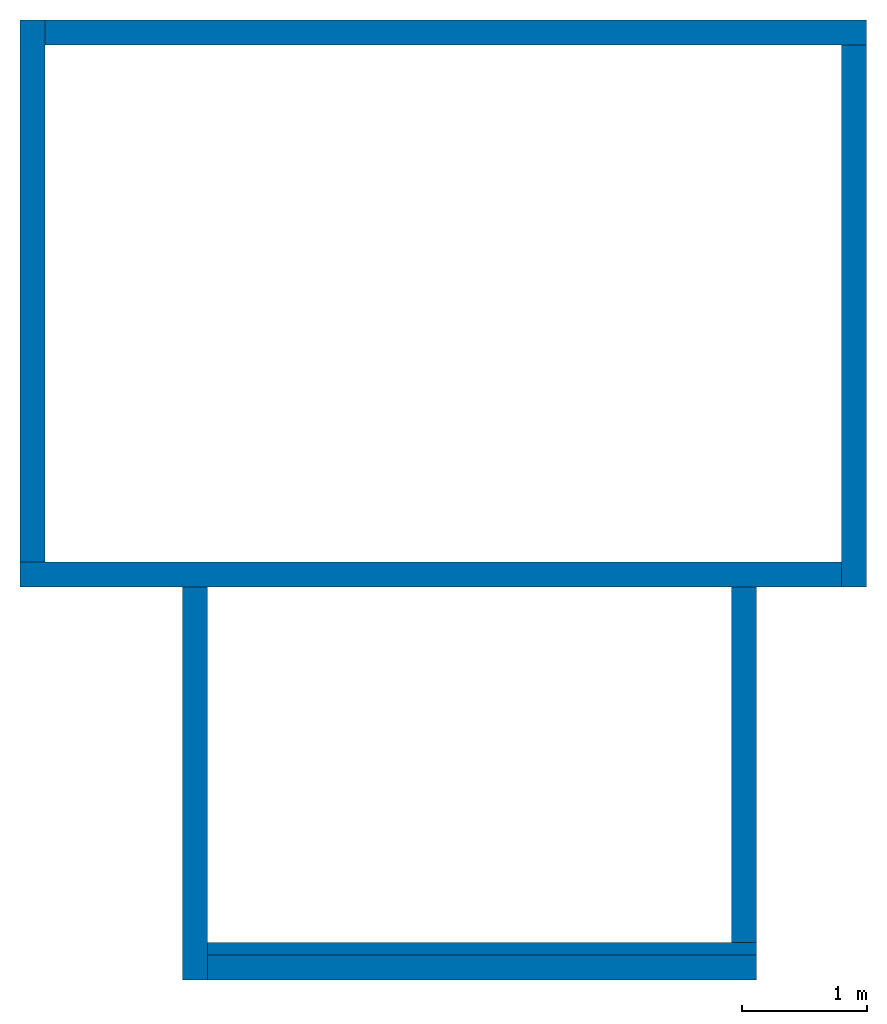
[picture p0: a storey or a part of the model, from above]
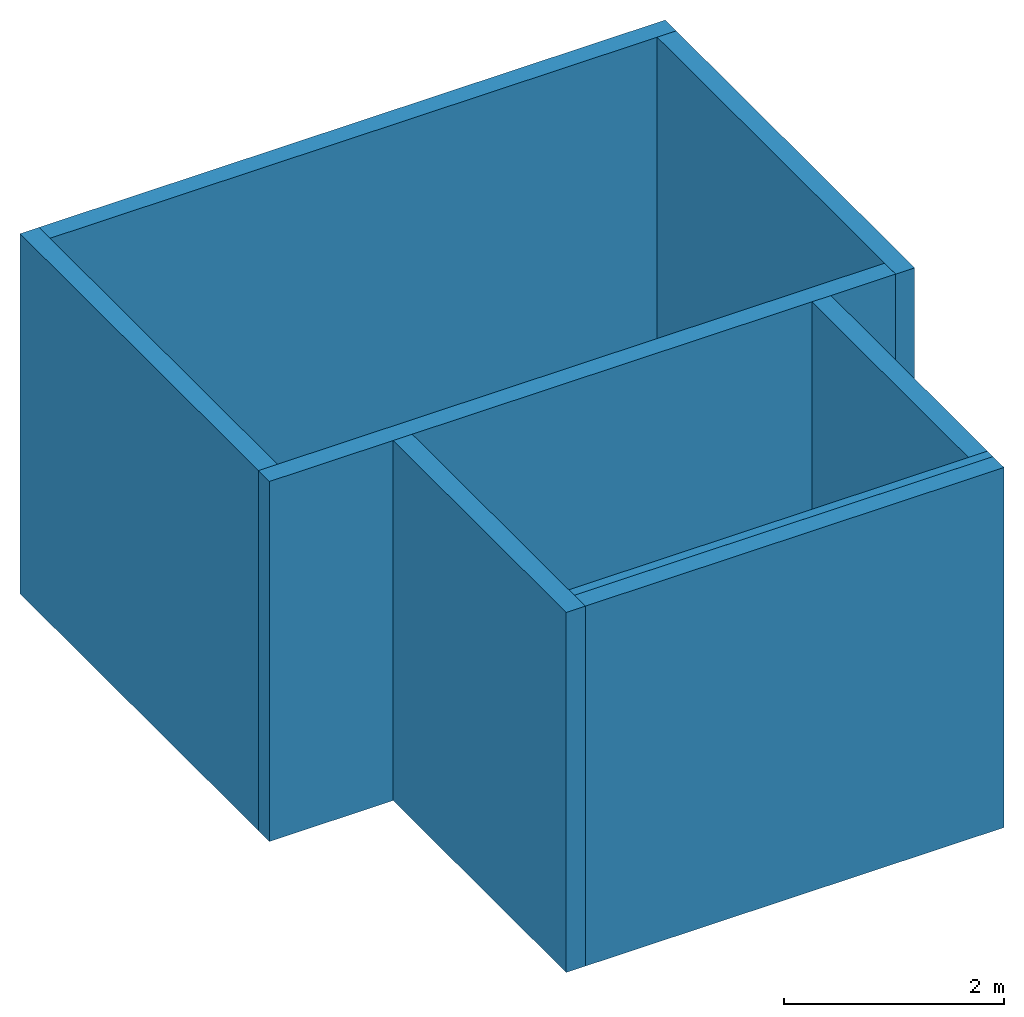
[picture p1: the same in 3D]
Properties of the parts of a building model (IFC2X3)

# File
Description: ViewDefinition [CoordinationView]
Time: 2013-11-23T08:37:47
Written by: The EXPRESS Data Manager Version 5.01.0100.02.64mod : 6 Jun 2012
Made in: 20130308_1515(x64) - Exporter 3.5.0.0 - Alternate UI 2.5.0.0
Comment: STEP Physical File produced by: The EXPRESS Data Manager Version 5.01.0100.02.64mod : 6 Jun 2012 * Module: EDMstepFileFactory/EDMstandAlone * Creation date: Sat Nov 23 08:37:47 2013 * Host: MDR_LPTP_BTO * Database: C:\Users\Martijn\AppData\Local\Temp\{DCC4B155-83EB-489F-8252-D7C3DF03CAA3}\ifc * Database version: 5507 * Database creation date: Sat Nov 23 08:37:47 2013 * Schema: IFC2X3 * Model: DataRepository.ifc * Model creation date: Sat Nov 23 08:37:47 2013 * Header model: DataRepository.ifc_HeaderModel * Header model creation date: Sat Nov 23 08:37:47 2013 * EDMuser: sdai-user * EDMgroup: sdai-group * License ID and type: 5605 : Permanent license. Expiry date: * EDMstepFileFactory options: 020000

# IfcProject
LongName: E:\MdR Advies\Google Drive\001 - Overige werkzaamheden\AU2013\files\testfile_Parts.ifc

# IfcSite, Default
RefLatitude: 42, 24, 53, 508911; RefLongitude: -71, -15, -29, -58837; RefElevation: 0 mm

# IfcBuilding
Pset_BuildingCommon - NumberOfStoreys: 1

# IfcBuildingStorey, Level 1
LongName: Level 1; Elevation: 0 mm
Constraints - Elevation: 0 mm; Elevation Base: Project Base Point
Dimensions - Computation Height: 0 mm
Identity Data - Building Story: yes; Name: Level 1; Structural: no
Graphics - Color: 0; Line Pattern: -3000010; Line Weight: 1; Symbol at End 1 Default: no; Symbol at End 2 Default: yes

# IfcWall (2)
In: Level 1
Material: Default Wall
Pset_WallCommon - Reference: Part; LoadBearing: no; ExtendToStructure: no; IsExternal: no
PSet_COBIE - NominalLength: 4400
Constraints - Base Level: Level: Level 1
Dimensions - Area: 17.6 m2; Excluded: no; Height: 4000 mm; Length: 4400 mm; Shape is modified: no
Identity Data - Construction: Core; Material: Default Wall; Material By Original: yes; Original Category: -2000011; Original Family: Basic Wall; Original Type: Wall 2; Show Shape Handles: no
Phasing - Phase Created: New Construction; Phase Created By Original: yes; Phase Demolished By Original: yes
Name (Part:...) | Thickness (mm) | Volume (m3)
2932 | 100 | 1.76
2933 | 200 | 3.52

# IfcWallStandardCase: Basic Wall:Wall 1 (6)
In: Level 1
Type - PredefinedType: STANDARD; Material: Default Wall 200 mm
Type - Analytical Properties - Absorptance: 0.1; Roughness: 1
Type - Construction - Function: Exterior; Width: 200 mm; Wrapping at Inserts: Do not wrap
Type - Graphics - Coarse Scale Fill Color: 0
Constraints - Base Constraint: Level: Level 1; Base Extension Distance: 0 mm; Base is Attached: no; Base Offset: 0 mm; Location Line: Wall Centerline; Related to Mass: no; Room Bounding: yes; Top Extension Distance: 0 mm; Top is Attached: no; Top Offset: 0 mm; Unconnected Height: 4000 mm
Phasing - Phase Created: New Construction
Structural - Enable Analytical Model: no; Structural: no; Structural Usage: Non-bearing
Pset_WallCommon - Reference: Wall 1; LoadBearing: no; ExtendToStructure: no; IsExternal: yes
PSet_COBIE - NominalWidth: 200
Name (Basic Wall:Wall 1:...) | Area (m2) | Length (mm) = NominalLength | Volume (m3)
2277 | 26.32 | 6580 | 5.264
2278 | 17.36 | 4340 | 3.472
2279 | 26.32 | 6580 | 5.264
2280 | 17.36 | 4340 | 3.472
2354 | 12.6 | 3100 | 2.52
2422 | 11.4 | 3100 | 2.28
